VERSION 5.7 ;
BUSBITCHARS "[]" ;
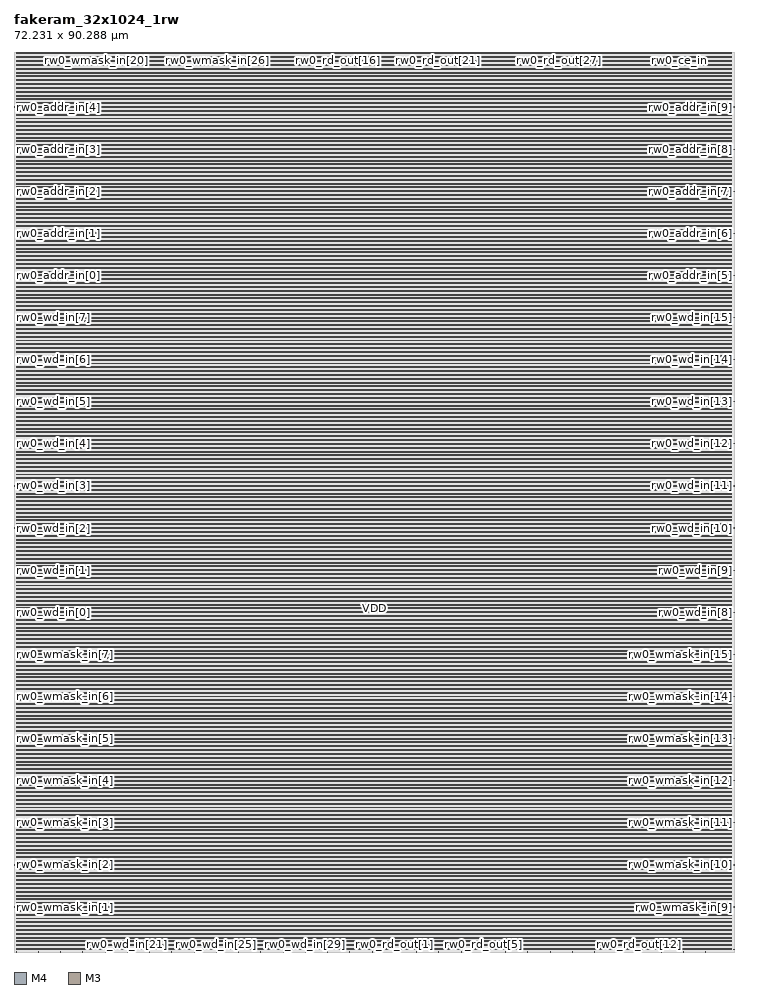
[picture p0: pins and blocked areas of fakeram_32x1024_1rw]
MACRO fakeram_32x1024_1rw
  FOREIGN fakeram_32x1024_1rw 0 0 ;
  SYMMETRY X Y R90 ;
  SIZE 72.231 BY 90.288 ;
  CLASS BLOCK ;
  PIN rw0_wmask_in[0]
    DIRECTION INPUT ;
    USE SIGNAL ;
    SHAPE ABUTMENT ;
    PORT
      LAYER M4 ;
      RECT 0.000 0.276 0.072 0.300 ;
    END
  END rw0_wmask_in[0]
  PIN rw0_wmask_in[1]
    DIRECTION INPUT ;
    USE SIGNAL ;
    SHAPE ABUTMENT ;
    PORT
      LAYER M4 ;
      RECT 0.000 4.500 0.072 4.524 ;
    END
  END rw0_wmask_in[1]
  PIN rw0_wmask_in[2]
    DIRECTION INPUT ;
    USE SIGNAL ;
    SHAPE ABUTMENT ;
    PORT
      LAYER M4 ;
      RECT 0.000 8.724 0.072 8.748 ;
    END
  END rw0_wmask_in[2]
  PIN rw0_wmask_in[3]
    DIRECTION INPUT ;
    USE SIGNAL ;
    SHAPE ABUTMENT ;
    PORT
      LAYER M4 ;
      RECT 0.000 12.948 0.072 12.972 ;
    END
  END rw0_wmask_in[3]
  PIN rw0_wmask_in[4]
    DIRECTION INPUT ;
    USE SIGNAL ;
    SHAPE ABUTMENT ;
    PORT
      LAYER M4 ;
      RECT 0.000 17.172 0.072 17.196 ;
    END
  END rw0_wmask_in[4]
  PIN rw0_wmask_in[5]
    DIRECTION INPUT ;
    USE SIGNAL ;
    SHAPE ABUTMENT ;
    PORT
      LAYER M4 ;
      RECT 0.000 21.396 0.072 21.420 ;
    END
  END rw0_wmask_in[5]
  PIN rw0_wmask_in[6]
    DIRECTION INPUT ;
    USE SIGNAL ;
    SHAPE ABUTMENT ;
    PORT
      LAYER M4 ;
      RECT 0.000 25.620 0.072 25.644 ;
    END
  END rw0_wmask_in[6]
  PIN rw0_wmask_in[7]
    DIRECTION INPUT ;
    USE SIGNAL ;
    SHAPE ABUTMENT ;
    PORT
      LAYER M4 ;
      RECT 0.000 29.844 0.072 29.868 ;
    END
  END rw0_wmask_in[7]
  PIN rw0_wmask_in[8]
    DIRECTION INPUT ;
    USE SIGNAL ;
    SHAPE ABUTMENT ;
    PORT
      LAYER M4 ;
      RECT 72.159 0.276 72.231 0.300 ;
    END
  END rw0_wmask_in[8]
  PIN rw0_wmask_in[9]
    DIRECTION INPUT ;
    USE SIGNAL ;
    SHAPE ABUTMENT ;
    PORT
      LAYER M4 ;
      RECT 72.159 4.500 72.231 4.524 ;
    END
  END rw0_wmask_in[9]
  PIN rw0_wmask_in[10]
    DIRECTION INPUT ;
    USE SIGNAL ;
    SHAPE ABUTMENT ;
    PORT
      LAYER M4 ;
      RECT 72.159 8.724 72.231 8.748 ;
    END
  END rw0_wmask_in[10]
  PIN rw0_wmask_in[11]
    DIRECTION INPUT ;
    USE SIGNAL ;
    SHAPE ABUTMENT ;
    PORT
      LAYER M4 ;
      RECT 72.159 12.948 72.231 12.972 ;
    END
  END rw0_wmask_in[11]
  PIN rw0_wmask_in[12]
    DIRECTION INPUT ;
    USE SIGNAL ;
    SHAPE ABUTMENT ;
    PORT
      LAYER M4 ;
      RECT 72.159 17.172 72.231 17.196 ;
    END
  END rw0_wmask_in[12]
  PIN rw0_wmask_in[13]
    DIRECTION INPUT ;
    USE SIGNAL ;
    SHAPE ABUTMENT ;
    PORT
      LAYER M4 ;
      RECT 72.159 21.396 72.231 21.420 ;
    END
  END rw0_wmask_in[13]
  PIN rw0_wmask_in[14]
    DIRECTION INPUT ;
    USE SIGNAL ;
    SHAPE ABUTMENT ;
    PORT
      LAYER M4 ;
      RECT 72.159 25.620 72.231 25.644 ;
    END
  END rw0_wmask_in[14]
  PIN rw0_wmask_in[15]
    DIRECTION INPUT ;
    USE SIGNAL ;
    SHAPE ABUTMENT ;
    PORT
      LAYER M4 ;
      RECT 72.159 29.844 72.231 29.868 ;
    END
  END rw0_wmask_in[15]
  PIN rw0_wmask_in[16]
    DIRECTION INPUT ;
    USE SIGNAL ;
    SHAPE ABUTMENT ;
    PORT
      LAYER M3 ;
      RECT 0.207 90.234 0.225 90.288 ;
    END
  END rw0_wmask_in[16]
  PIN rw0_wmask_in[17]
    DIRECTION INPUT ;
    USE SIGNAL ;
    SHAPE ABUTMENT ;
    PORT
      LAYER M3 ;
      RECT 2.223 90.234 2.241 90.288 ;
    END
  END rw0_wmask_in[17]
  PIN rw0_wmask_in[18]
    DIRECTION INPUT ;
    USE SIGNAL ;
    SHAPE ABUTMENT ;
    PORT
      LAYER M3 ;
      RECT 4.239 90.234 4.257 90.288 ;
    END
  END rw0_wmask_in[18]
  PIN rw0_wmask_in[19]
    DIRECTION INPUT ;
    USE SIGNAL ;
    SHAPE ABUTMENT ;
    PORT
      LAYER M3 ;
      RECT 6.255 90.234 6.273 90.288 ;
    END
  END rw0_wmask_in[19]
  PIN rw0_wmask_in[20]
    DIRECTION INPUT ;
    USE SIGNAL ;
    SHAPE ABUTMENT ;
    PORT
      LAYER M3 ;
      RECT 8.271 90.234 8.289 90.288 ;
    END
  END rw0_wmask_in[20]
  PIN rw0_wmask_in[21]
    DIRECTION INPUT ;
    USE SIGNAL ;
    SHAPE ABUTMENT ;
    PORT
      LAYER M3 ;
      RECT 10.287 90.234 10.305 90.288 ;
    END
  END rw0_wmask_in[21]
  PIN rw0_wmask_in[22]
    DIRECTION INPUT ;
    USE SIGNAL ;
    SHAPE ABUTMENT ;
    PORT
      LAYER M3 ;
      RECT 12.303 90.234 12.321 90.288 ;
    END
  END rw0_wmask_in[22]
  PIN rw0_wmask_in[23]
    DIRECTION INPUT ;
    USE SIGNAL ;
    SHAPE ABUTMENT ;
    PORT
      LAYER M3 ;
      RECT 14.319 90.234 14.337 90.288 ;
    END
  END rw0_wmask_in[23]
  PIN rw0_wmask_in[24]
    DIRECTION INPUT ;
    USE SIGNAL ;
    SHAPE ABUTMENT ;
    PORT
      LAYER M3 ;
      RECT 16.335 90.234 16.353 90.288 ;
    END
  END rw0_wmask_in[24]
  PIN rw0_wmask_in[25]
    DIRECTION INPUT ;
    USE SIGNAL ;
    SHAPE ABUTMENT ;
    PORT
      LAYER M3 ;
      RECT 18.351 90.234 18.369 90.288 ;
    END
  END rw0_wmask_in[25]
  PIN rw0_wmask_in[26]
    DIRECTION INPUT ;
    USE SIGNAL ;
    SHAPE ABUTMENT ;
    PORT
      LAYER M3 ;
      RECT 20.367 90.234 20.385 90.288 ;
    END
  END rw0_wmask_in[26]
  PIN rw0_wmask_in[27]
    DIRECTION INPUT ;
    USE SIGNAL ;
    SHAPE ABUTMENT ;
    PORT
      LAYER M3 ;
      RECT 22.383 90.234 22.401 90.288 ;
    END
  END rw0_wmask_in[27]
  PIN rw0_wmask_in[28]
    DIRECTION INPUT ;
    USE SIGNAL ;
    SHAPE ABUTMENT ;
    PORT
      LAYER M3 ;
      RECT 24.399 90.234 24.417 90.288 ;
    END
  END rw0_wmask_in[28]
  PIN rw0_wmask_in[29]
    DIRECTION INPUT ;
    USE SIGNAL ;
    SHAPE ABUTMENT ;
    PORT
      LAYER M3 ;
      RECT 26.415 90.234 26.433 90.288 ;
    END
  END rw0_wmask_in[29]
  PIN rw0_wmask_in[30]
    DIRECTION INPUT ;
    USE SIGNAL ;
    SHAPE ABUTMENT ;
    PORT
      LAYER M3 ;
      RECT 28.431 90.234 28.449 90.288 ;
    END
  END rw0_wmask_in[30]
  PIN rw0_wmask_in[31]
    DIRECTION INPUT ;
    USE SIGNAL ;
    SHAPE ABUTMENT ;
    PORT
      LAYER M3 ;
      RECT 30.447 90.234 30.465 90.288 ;
    END
  END rw0_wmask_in[31]
  PIN rw0_wd_in[0]
    DIRECTION INPUT ;
    USE SIGNAL ;
    SHAPE ABUTMENT ;
    PORT
      LAYER M4 ;
      RECT 0.000 34.068 0.072 34.092 ;
    END
  END rw0_wd_in[0]
  PIN rw0_wd_in[1]
    DIRECTION INPUT ;
    USE SIGNAL ;
    SHAPE ABUTMENT ;
    PORT
      LAYER M4 ;
      RECT 0.000 38.292 0.072 38.316 ;
    END
  END rw0_wd_in[1]
  PIN rw0_wd_in[2]
    DIRECTION INPUT ;
    USE SIGNAL ;
    SHAPE ABUTMENT ;
    PORT
      LAYER M4 ;
      RECT 0.000 42.516 0.072 42.540 ;
    END
  END rw0_wd_in[2]
  PIN rw0_wd_in[3]
    DIRECTION INPUT ;
    USE SIGNAL ;
    SHAPE ABUTMENT ;
    PORT
      LAYER M4 ;
      RECT 0.000 46.740 0.072 46.764 ;
    END
  END rw0_wd_in[3]
  PIN rw0_wd_in[4]
    DIRECTION INPUT ;
    USE SIGNAL ;
    SHAPE ABUTMENT ;
    PORT
      LAYER M4 ;
      RECT 0.000 50.964 0.072 50.988 ;
    END
  END rw0_wd_in[4]
  PIN rw0_wd_in[5]
    DIRECTION INPUT ;
    USE SIGNAL ;
    SHAPE ABUTMENT ;
    PORT
      LAYER M4 ;
      RECT 0.000 55.188 0.072 55.212 ;
    END
  END rw0_wd_in[5]
  PIN rw0_wd_in[6]
    DIRECTION INPUT ;
    USE SIGNAL ;
    SHAPE ABUTMENT ;
    PORT
      LAYER M4 ;
      RECT 0.000 59.412 0.072 59.436 ;
    END
  END rw0_wd_in[6]
  PIN rw0_wd_in[7]
    DIRECTION INPUT ;
    USE SIGNAL ;
    SHAPE ABUTMENT ;
    PORT
      LAYER M4 ;
      RECT 0.000 63.636 0.072 63.660 ;
    END
  END rw0_wd_in[7]
  PIN rw0_wd_in[8]
    DIRECTION INPUT ;
    USE SIGNAL ;
    SHAPE ABUTMENT ;
    PORT
      LAYER M4 ;
      RECT 72.159 34.068 72.231 34.092 ;
    END
  END rw0_wd_in[8]
  PIN rw0_wd_in[9]
    DIRECTION INPUT ;
    USE SIGNAL ;
    SHAPE ABUTMENT ;
    PORT
      LAYER M4 ;
      RECT 72.159 38.292 72.231 38.316 ;
    END
  END rw0_wd_in[9]
  PIN rw0_wd_in[10]
    DIRECTION INPUT ;
    USE SIGNAL ;
    SHAPE ABUTMENT ;
    PORT
      LAYER M4 ;
      RECT 72.159 42.516 72.231 42.540 ;
    END
  END rw0_wd_in[10]
  PIN rw0_wd_in[11]
    DIRECTION INPUT ;
    USE SIGNAL ;
    SHAPE ABUTMENT ;
    PORT
      LAYER M4 ;
      RECT 72.159 46.740 72.231 46.764 ;
    END
  END rw0_wd_in[11]
  PIN rw0_wd_in[12]
    DIRECTION INPUT ;
    USE SIGNAL ;
    SHAPE ABUTMENT ;
    PORT
      LAYER M4 ;
      RECT 72.159 50.964 72.231 50.988 ;
    END
  END rw0_wd_in[12]
  PIN rw0_wd_in[13]
    DIRECTION INPUT ;
    USE SIGNAL ;
    SHAPE ABUTMENT ;
    PORT
      LAYER M4 ;
      RECT 72.159 55.188 72.231 55.212 ;
    END
  END rw0_wd_in[13]
  PIN rw0_wd_in[14]
    DIRECTION INPUT ;
    USE SIGNAL ;
    SHAPE ABUTMENT ;
    PORT
      LAYER M4 ;
      RECT 72.159 59.412 72.231 59.436 ;
    END
  END rw0_wd_in[14]
  PIN rw0_wd_in[15]
    DIRECTION INPUT ;
    USE SIGNAL ;
    SHAPE ABUTMENT ;
    PORT
      LAYER M4 ;
      RECT 72.159 63.636 72.231 63.660 ;
    END
  END rw0_wd_in[15]
  PIN rw0_wd_in[16]
    DIRECTION INPUT ;
    USE SIGNAL ;
    SHAPE ABUTMENT ;
    PORT
      LAYER M3 ;
      RECT 0.207 0.000 0.225 0.054 ;
    END
  END rw0_wd_in[16]
  PIN rw0_wd_in[17]
    DIRECTION INPUT ;
    USE SIGNAL ;
    SHAPE ABUTMENT ;
    PORT
      LAYER M3 ;
      RECT 2.439 0.000 2.457 0.054 ;
    END
  END rw0_wd_in[17]
  PIN rw0_wd_in[18]
    DIRECTION INPUT ;
    USE SIGNAL ;
    SHAPE ABUTMENT ;
    PORT
      LAYER M3 ;
      RECT 4.671 0.000 4.689 0.054 ;
    END
  END rw0_wd_in[18]
  PIN rw0_wd_in[19]
    DIRECTION INPUT ;
    USE SIGNAL ;
    SHAPE ABUTMENT ;
    PORT
      LAYER M3 ;
      RECT 6.903 0.000 6.921 0.054 ;
    END
  END rw0_wd_in[19]
  PIN rw0_wd_in[20]
    DIRECTION INPUT ;
    USE SIGNAL ;
    SHAPE ABUTMENT ;
    PORT
      LAYER M3 ;
      RECT 9.135 0.000 9.153 0.054 ;
    END
  END rw0_wd_in[20]
  PIN rw0_wd_in[21]
    DIRECTION INPUT ;
    USE SIGNAL ;
    SHAPE ABUTMENT ;
    PORT
      LAYER M3 ;
      RECT 11.367 0.000 11.385 0.054 ;
    END
  END rw0_wd_in[21]
  PIN rw0_wd_in[22]
    DIRECTION INPUT ;
    USE SIGNAL ;
    SHAPE ABUTMENT ;
    PORT
      LAYER M3 ;
      RECT 13.599 0.000 13.617 0.054 ;
    END
  END rw0_wd_in[22]
  PIN rw0_wd_in[23]
    DIRECTION INPUT ;
    USE SIGNAL ;
    SHAPE ABUTMENT ;
    PORT
      LAYER M3 ;
      RECT 15.831 0.000 15.849 0.054 ;
    END
  END rw0_wd_in[23]
  PIN rw0_wd_in[24]
    DIRECTION INPUT ;
    USE SIGNAL ;
    SHAPE ABUTMENT ;
    PORT
      LAYER M3 ;
      RECT 18.063 0.000 18.081 0.054 ;
    END
  END rw0_wd_in[24]
  PIN rw0_wd_in[25]
    DIRECTION INPUT ;
    USE SIGNAL ;
    SHAPE ABUTMENT ;
    PORT
      LAYER M3 ;
      RECT 20.295 0.000 20.313 0.054 ;
    END
  END rw0_wd_in[25]
  PIN rw0_wd_in[26]
    DIRECTION INPUT ;
    USE SIGNAL ;
    SHAPE ABUTMENT ;
    PORT
      LAYER M3 ;
      RECT 22.527 0.000 22.545 0.054 ;
    END
  END rw0_wd_in[26]
  PIN rw0_wd_in[27]
    DIRECTION INPUT ;
    USE SIGNAL ;
    SHAPE ABUTMENT ;
    PORT
      LAYER M3 ;
      RECT 24.759 0.000 24.777 0.054 ;
    END
  END rw0_wd_in[27]
  PIN rw0_wd_in[28]
    DIRECTION INPUT ;
    USE SIGNAL ;
    SHAPE ABUTMENT ;
    PORT
      LAYER M3 ;
      RECT 26.991 0.000 27.009 0.054 ;
    END
  END rw0_wd_in[28]
  PIN rw0_wd_in[29]
    DIRECTION INPUT ;
    USE SIGNAL ;
    SHAPE ABUTMENT ;
    PORT
      LAYER M3 ;
      RECT 29.223 0.000 29.241 0.054 ;
    END
  END rw0_wd_in[29]
  PIN rw0_wd_in[30]
    DIRECTION INPUT ;
    USE SIGNAL ;
    SHAPE ABUTMENT ;
    PORT
      LAYER M3 ;
      RECT 31.455 0.000 31.473 0.054 ;
    END
  END rw0_wd_in[30]
  PIN rw0_wd_in[31]
    DIRECTION INPUT ;
    USE SIGNAL ;
    SHAPE ABUTMENT ;
    PORT
      LAYER M3 ;
      RECT 33.687 0.000 33.705 0.054 ;
    END
  END rw0_wd_in[31]
  PIN rw0_rd_out[0]
    DIRECTION OUTPUT ;
    USE SIGNAL ;
    SHAPE ABUTMENT ;
    PORT
      LAYER M3 ;
      RECT 35.919 0.000 35.937 0.054 ;
    END
  END rw0_rd_out[0]
  PIN rw0_rd_out[1]
    DIRECTION OUTPUT ;
    USE SIGNAL ;
    SHAPE ABUTMENT ;
    PORT
      LAYER M3 ;
      RECT 38.151 0.000 38.169 0.054 ;
    END
  END rw0_rd_out[1]
  PIN rw0_rd_out[2]
    DIRECTION OUTPUT ;
    USE SIGNAL ;
    SHAPE ABUTMENT ;
    PORT
      LAYER M3 ;
      RECT 40.383 0.000 40.401 0.054 ;
    END
  END rw0_rd_out[2]
  PIN rw0_rd_out[3]
    DIRECTION OUTPUT ;
    USE SIGNAL ;
    SHAPE ABUTMENT ;
    PORT
      LAYER M3 ;
      RECT 42.615 0.000 42.633 0.054 ;
    END
  END rw0_rd_out[3]
  PIN rw0_rd_out[4]
    DIRECTION OUTPUT ;
    USE SIGNAL ;
    SHAPE ABUTMENT ;
    PORT
      LAYER M3 ;
      RECT 44.847 0.000 44.865 0.054 ;
    END
  END rw0_rd_out[4]
  PIN rw0_rd_out[5]
    DIRECTION OUTPUT ;
    USE SIGNAL ;
    SHAPE ABUTMENT ;
    PORT
      LAYER M3 ;
      RECT 47.079 0.000 47.097 0.054 ;
    END
  END rw0_rd_out[5]
  PIN rw0_rd_out[6]
    DIRECTION OUTPUT ;
    USE SIGNAL ;
    SHAPE ABUTMENT ;
    PORT
      LAYER M3 ;
      RECT 49.311 0.000 49.329 0.054 ;
    END
  END rw0_rd_out[6]
  PIN rw0_rd_out[7]
    DIRECTION OUTPUT ;
    USE SIGNAL ;
    SHAPE ABUTMENT ;
    PORT
      LAYER M3 ;
      RECT 51.543 0.000 51.561 0.054 ;
    END
  END rw0_rd_out[7]
  PIN rw0_rd_out[8]
    DIRECTION OUTPUT ;
    USE SIGNAL ;
    SHAPE ABUTMENT ;
    PORT
      LAYER M3 ;
      RECT 53.775 0.000 53.793 0.054 ;
    END
  END rw0_rd_out[8]
  PIN rw0_rd_out[9]
    DIRECTION OUTPUT ;
    USE SIGNAL ;
    SHAPE ABUTMENT ;
    PORT
      LAYER M3 ;
      RECT 56.007 0.000 56.025 0.054 ;
    END
  END rw0_rd_out[9]
  PIN rw0_rd_out[10]
    DIRECTION OUTPUT ;
    USE SIGNAL ;
    SHAPE ABUTMENT ;
    PORT
      LAYER M3 ;
      RECT 58.239 0.000 58.257 0.054 ;
    END
  END rw0_rd_out[10]
  PIN rw0_rd_out[11]
    DIRECTION OUTPUT ;
    USE SIGNAL ;
    SHAPE ABUTMENT ;
    PORT
      LAYER M3 ;
      RECT 60.471 0.000 60.489 0.054 ;
    END
  END rw0_rd_out[11]
  PIN rw0_rd_out[12]
    DIRECTION OUTPUT ;
    USE SIGNAL ;
    SHAPE ABUTMENT ;
    PORT
      LAYER M3 ;
      RECT 62.703 0.000 62.721 0.054 ;
    END
  END rw0_rd_out[12]
  PIN rw0_rd_out[13]
    DIRECTION OUTPUT ;
    USE SIGNAL ;
    SHAPE ABUTMENT ;
    PORT
      LAYER M3 ;
      RECT 64.935 0.000 64.953 0.054 ;
    END
  END rw0_rd_out[13]
  PIN rw0_rd_out[14]
    DIRECTION OUTPUT ;
    USE SIGNAL ;
    SHAPE ABUTMENT ;
    PORT
      LAYER M3 ;
      RECT 67.167 0.000 67.185 0.054 ;
    END
  END rw0_rd_out[14]
  PIN rw0_rd_out[15]
    DIRECTION OUTPUT ;
    USE SIGNAL ;
    SHAPE ABUTMENT ;
    PORT
      LAYER M3 ;
      RECT 69.399 0.000 69.417 0.054 ;
    END
  END rw0_rd_out[15]
  PIN rw0_rd_out[16]
    DIRECTION OUTPUT ;
    USE SIGNAL ;
    SHAPE ABUTMENT ;
    PORT
      LAYER M3 ;
      RECT 32.463 90.234 32.481 90.288 ;
    END
  END rw0_rd_out[16]
  PIN rw0_rd_out[17]
    DIRECTION OUTPUT ;
    USE SIGNAL ;
    SHAPE ABUTMENT ;
    PORT
      LAYER M3 ;
      RECT 34.479 90.234 34.497 90.288 ;
    END
  END rw0_rd_out[17]
  PIN rw0_rd_out[18]
    DIRECTION OUTPUT ;
    USE SIGNAL ;
    SHAPE ABUTMENT ;
    PORT
      LAYER M3 ;
      RECT 36.495 90.234 36.513 90.288 ;
    END
  END rw0_rd_out[18]
  PIN rw0_rd_out[19]
    DIRECTION OUTPUT ;
    USE SIGNAL ;
    SHAPE ABUTMENT ;
    PORT
      LAYER M3 ;
      RECT 38.511 90.234 38.529 90.288 ;
    END
  END rw0_rd_out[19]
  PIN rw0_rd_out[20]
    DIRECTION OUTPUT ;
    USE SIGNAL ;
    SHAPE ABUTMENT ;
    PORT
      LAYER M3 ;
      RECT 40.527 90.234 40.545 90.288 ;
    END
  END rw0_rd_out[20]
  PIN rw0_rd_out[21]
    DIRECTION OUTPUT ;
    USE SIGNAL ;
    SHAPE ABUTMENT ;
    PORT
      LAYER M3 ;
      RECT 42.543 90.234 42.561 90.288 ;
    END
  END rw0_rd_out[21]
  PIN rw0_rd_out[22]
    DIRECTION OUTPUT ;
    USE SIGNAL ;
    SHAPE ABUTMENT ;
    PORT
      LAYER M3 ;
      RECT 44.559 90.234 44.577 90.288 ;
    END
  END rw0_rd_out[22]
  PIN rw0_rd_out[23]
    DIRECTION OUTPUT ;
    USE SIGNAL ;
    SHAPE ABUTMENT ;
    PORT
      LAYER M3 ;
      RECT 46.575 90.234 46.593 90.288 ;
    END
  END rw0_rd_out[23]
  PIN rw0_rd_out[24]
    DIRECTION OUTPUT ;
    USE SIGNAL ;
    SHAPE ABUTMENT ;
    PORT
      LAYER M3 ;
      RECT 48.591 90.234 48.609 90.288 ;
    END
  END rw0_rd_out[24]
  PIN rw0_rd_out[25]
    DIRECTION OUTPUT ;
    USE SIGNAL ;
    SHAPE ABUTMENT ;
    PORT
      LAYER M3 ;
      RECT 50.607 90.234 50.625 90.288 ;
    END
  END rw0_rd_out[25]
  PIN rw0_rd_out[26]
    DIRECTION OUTPUT ;
    USE SIGNAL ;
    SHAPE ABUTMENT ;
    PORT
      LAYER M3 ;
      RECT 52.623 90.234 52.641 90.288 ;
    END
  END rw0_rd_out[26]
  PIN rw0_rd_out[27]
    DIRECTION OUTPUT ;
    USE SIGNAL ;
    SHAPE ABUTMENT ;
    PORT
      LAYER M3 ;
      RECT 54.639 90.234 54.657 90.288 ;
    END
  END rw0_rd_out[27]
  PIN rw0_rd_out[28]
    DIRECTION OUTPUT ;
    USE SIGNAL ;
    SHAPE ABUTMENT ;
    PORT
      LAYER M3 ;
      RECT 56.655 90.234 56.673 90.288 ;
    END
  END rw0_rd_out[28]
  PIN rw0_rd_out[29]
    DIRECTION OUTPUT ;
    USE SIGNAL ;
    SHAPE ABUTMENT ;
    PORT
      LAYER M3 ;
      RECT 58.671 90.234 58.689 90.288 ;
    END
  END rw0_rd_out[29]
  PIN rw0_rd_out[30]
    DIRECTION OUTPUT ;
    USE SIGNAL ;
    SHAPE ABUTMENT ;
    PORT
      LAYER M3 ;
      RECT 60.687 90.234 60.705 90.288 ;
    END
  END rw0_rd_out[30]
  PIN rw0_rd_out[31]
    DIRECTION OUTPUT ;
    USE SIGNAL ;
    SHAPE ABUTMENT ;
    PORT
      LAYER M3 ;
      RECT 62.703 90.234 62.721 90.288 ;
    END
  END rw0_rd_out[31]
  PIN rw0_addr_in[0]
    DIRECTION INPUT ;
    USE SIGNAL ;
    SHAPE ABUTMENT ;
    PORT
      LAYER M4 ;
      RECT 0.000 67.860 0.072 67.884 ;
    END
  END rw0_addr_in[0]
  PIN rw0_addr_in[1]
    DIRECTION INPUT ;
    USE SIGNAL ;
    SHAPE ABUTMENT ;
    PORT
      LAYER M4 ;
      RECT 0.000 72.084 0.072 72.108 ;
    END
  END rw0_addr_in[1]
  PIN rw0_addr_in[2]
    DIRECTION INPUT ;
    USE SIGNAL ;
    SHAPE ABUTMENT ;
    PORT
      LAYER M4 ;
      RECT 0.000 76.308 0.072 76.332 ;
    END
  END rw0_addr_in[2]
  PIN rw0_addr_in[3]
    DIRECTION INPUT ;
    USE SIGNAL ;
    SHAPE ABUTMENT ;
    PORT
      LAYER M4 ;
      RECT 0.000 80.532 0.072 80.556 ;
    END
  END rw0_addr_in[3]
  PIN rw0_addr_in[4]
    DIRECTION INPUT ;
    USE SIGNAL ;
    SHAPE ABUTMENT ;
    PORT
      LAYER M4 ;
      RECT 0.000 84.756 0.072 84.780 ;
    END
  END rw0_addr_in[4]
  PIN rw0_addr_in[5]
    DIRECTION INPUT ;
    USE SIGNAL ;
    SHAPE ABUTMENT ;
    PORT
      LAYER M4 ;
      RECT 72.159 67.860 72.231 67.884 ;
    END
  END rw0_addr_in[5]
  PIN rw0_addr_in[6]
    DIRECTION INPUT ;
    USE SIGNAL ;
    SHAPE ABUTMENT ;
    PORT
      LAYER M4 ;
      RECT 72.159 72.084 72.231 72.108 ;
    END
  END rw0_addr_in[6]
  PIN rw0_addr_in[7]
    DIRECTION INPUT ;
    USE SIGNAL ;
    SHAPE ABUTMENT ;
    PORT
      LAYER M4 ;
      RECT 72.159 76.308 72.231 76.332 ;
    END
  END rw0_addr_in[7]
  PIN rw0_addr_in[8]
    DIRECTION INPUT ;
    USE SIGNAL ;
    SHAPE ABUTMENT ;
    PORT
      LAYER M4 ;
      RECT 72.159 80.532 72.231 80.556 ;
    END
  END rw0_addr_in[8]
  PIN rw0_addr_in[9]
    DIRECTION INPUT ;
    USE SIGNAL ;
    SHAPE ABUTMENT ;
    PORT
      LAYER M4 ;
      RECT 72.159 84.756 72.231 84.780 ;
    END
  END rw0_addr_in[9]
  PIN rw0_we_in
    DIRECTION INPUT ;
    USE SIGNAL ;
    SHAPE ABUTMENT ;
    PORT
      LAYER M3 ;
      RECT 64.719 90.234 64.737 90.288 ;
    END
  END rw0_we_in
  PIN rw0_ce_in
    DIRECTION INPUT ;
    USE SIGNAL ;
    SHAPE ABUTMENT ;
    PORT
      LAYER M3 ;
      RECT 66.735 90.234 66.753 90.288 ;
    END
  END rw0_ce_in
  PIN rw0_clk
    DIRECTION INPUT ;
    USE SIGNAL ;
    SHAPE ABUTMENT ;
    PORT
      LAYER M3 ;
      RECT 68.751 90.234 68.769 90.288 ;
    END
  END rw0_clk
  PIN VSS
    DIRECTION INOUT ;
    USE GROUND ;
    PORT
      LAYER M4 ;
      RECT 0.216 0.240 72.015 0.336 ;
      RECT 0.216 1.008 72.015 1.104 ;
      RECT 0.216 1.776 72.015 1.872 ;
      RECT 0.216 2.544 72.015 2.640 ;
      RECT 0.216 3.312 72.015 3.408 ;
      RECT 0.216 4.080 72.015 4.176 ;
      RECT 0.216 4.848 72.015 4.944 ;
      RECT 0.216 5.616 72.015 5.712 ;
      RECT 0.216 6.384 72.015 6.480 ;
      RECT 0.216 7.152 72.015 7.248 ;
      RECT 0.216 7.920 72.015 8.016 ;
      RECT 0.216 8.688 72.015 8.784 ;
      RECT 0.216 9.456 72.015 9.552 ;
      RECT 0.216 10.224 72.015 10.320 ;
      RECT 0.216 10.992 72.015 11.088 ;
      RECT 0.216 11.760 72.015 11.856 ;
      RECT 0.216 12.528 72.015 12.624 ;
      RECT 0.216 13.296 72.015 13.392 ;
      RECT 0.216 14.064 72.015 14.160 ;
      RECT 0.216 14.832 72.015 14.928 ;
      RECT 0.216 15.600 72.015 15.696 ;
      RECT 0.216 16.368 72.015 16.464 ;
      RECT 0.216 17.136 72.015 17.232 ;
      RECT 0.216 17.904 72.015 18.000 ;
      RECT 0.216 18.672 72.015 18.768 ;
      RECT 0.216 19.440 72.015 19.536 ;
      RECT 0.216 20.208 72.015 20.304 ;
      RECT 0.216 20.976 72.015 21.072 ;
      RECT 0.216 21.744 72.015 21.840 ;
      RECT 0.216 22.512 72.015 22.608 ;
      RECT 0.216 23.280 72.015 23.376 ;
      RECT 0.216 24.048 72.015 24.144 ;
      RECT 0.216 24.816 72.015 24.912 ;
      RECT 0.216 25.584 72.015 25.680 ;
      RECT 0.216 26.352 72.015 26.448 ;
      RECT 0.216 27.120 72.015 27.216 ;
      RECT 0.216 27.888 72.015 27.984 ;
      RECT 0.216 28.656 72.015 28.752 ;
      RECT 0.216 29.424 72.015 29.520 ;
      RECT 0.216 30.192 72.015 30.288 ;
      RECT 0.216 30.960 72.015 31.056 ;
      RECT 0.216 31.728 72.015 31.824 ;
      RECT 0.216 32.496 72.015 32.592 ;
      RECT 0.216 33.264 72.015 33.360 ;
      RECT 0.216 34.032 72.015 34.128 ;
      RECT 0.216 34.800 72.015 34.896 ;
      RECT 0.216 35.568 72.015 35.664 ;
      RECT 0.216 36.336 72.015 36.432 ;
      RECT 0.216 37.104 72.015 37.200 ;
      RECT 0.216 37.872 72.015 37.968 ;
      RECT 0.216 38.640 72.015 38.736 ;
      RECT 0.216 39.408 72.015 39.504 ;
      RECT 0.216 40.176 72.015 40.272 ;
      RECT 0.216 40.944 72.015 41.040 ;
      RECT 0.216 41.712 72.015 41.808 ;
      RECT 0.216 42.480 72.015 42.576 ;
      RECT 0.216 43.248 72.015 43.344 ;
      RECT 0.216 44.016 72.015 44.112 ;
      RECT 0.216 44.784 72.015 44.880 ;
      RECT 0.216 45.552 72.015 45.648 ;
      RECT 0.216 46.320 72.015 46.416 ;
      RECT 0.216 47.088 72.015 47.184 ;
      RECT 0.216 47.856 72.015 47.952 ;
      RECT 0.216 48.624 72.015 48.720 ;
      RECT 0.216 49.392 72.015 49.488 ;
      RECT 0.216 50.160 72.015 50.256 ;
      RECT 0.216 50.928 72.015 51.024 ;
      RECT 0.216 51.696 72.015 51.792 ;
      RECT 0.216 52.464 72.015 52.560 ;
      RECT 0.216 53.232 72.015 53.328 ;
      RECT 0.216 54.000 72.015 54.096 ;
      RECT 0.216 54.768 72.015 54.864 ;
      RECT 0.216 55.536 72.015 55.632 ;
      RECT 0.216 56.304 72.015 56.400 ;
      RECT 0.216 57.072 72.015 57.168 ;
      RECT 0.216 57.840 72.015 57.936 ;
      RECT 0.216 58.608 72.015 58.704 ;
      RECT 0.216 59.376 72.015 59.472 ;
      RECT 0.216 60.144 72.015 60.240 ;
      RECT 0.216 60.912 72.015 61.008 ;
      RECT 0.216 61.680 72.015 61.776 ;
      RECT 0.216 62.448 72.015 62.544 ;
      RECT 0.216 63.216 72.015 63.312 ;
      RECT 0.216 63.984 72.015 64.080 ;
      RECT 0.216 64.752 72.015 64.848 ;
      RECT 0.216 65.520 72.015 65.616 ;
      RECT 0.216 66.288 72.015 66.384 ;
      RECT 0.216 67.056 72.015 67.152 ;
      RECT 0.216 67.824 72.015 67.920 ;
      RECT 0.216 68.592 72.015 68.688 ;
      RECT 0.216 69.360 72.015 69.456 ;
      RECT 0.216 70.128 72.015 70.224 ;
      RECT 0.216 70.896 72.015 70.992 ;
      RECT 0.216 71.664 72.015 71.760 ;
      RECT 0.216 72.432 72.015 72.528 ;
      RECT 0.216 73.200 72.015 73.296 ;
      RECT 0.216 73.968 72.015 74.064 ;
      RECT 0.216 74.736 72.015 74.832 ;
      RECT 0.216 75.504 72.015 75.600 ;
      RECT 0.216 76.272 72.015 76.368 ;
      RECT 0.216 77.040 72.015 77.136 ;
      RECT 0.216 77.808 72.015 77.904 ;
      RECT 0.216 78.576 72.015 78.672 ;
      RECT 0.216 79.344 72.015 79.440 ;
      RECT 0.216 80.112 72.015 80.208 ;
      RECT 0.216 80.880 72.015 80.976 ;
      RECT 0.216 81.648 72.015 81.744 ;
      RECT 0.216 82.416 72.015 82.512 ;
      RECT 0.216 83.184 72.015 83.280 ;
      RECT 0.216 83.952 72.015 84.048 ;
      RECT 0.216 84.720 72.015 84.816 ;
      RECT 0.216 85.488 72.015 85.584 ;
      RECT 0.216 86.256 72.015 86.352 ;
      RECT 0.216 87.024 72.015 87.120 ;
      RECT 0.216 87.792 72.015 87.888 ;
      RECT 0.216 88.560 72.015 88.656 ;
      RECT 0.216 89.328 72.015 89.424 ;
      RECT 0.216 90.096 72.015 90.192 ;
    END
  END VSS
  PIN VDD
    DIRECTION INOUT ;
    USE POWER ;
    PORT
      LAYER M4 ;
      RECT 0.216 0.624 72.015 0.720 ;
      RECT 0.216 1.392 72.015 1.488 ;
      RECT 0.216 2.160 72.015 2.256 ;
      RECT 0.216 2.928 72.015 3.024 ;
      RECT 0.216 3.696 72.015 3.792 ;
      RECT 0.216 4.464 72.015 4.560 ;
      RECT 0.216 5.232 72.015 5.328 ;
      RECT 0.216 6.000 72.015 6.096 ;
      RECT 0.216 6.768 72.015 6.864 ;
      RECT 0.216 7.536 72.015 7.632 ;
      RECT 0.216 8.304 72.015 8.400 ;
      RECT 0.216 9.072 72.015 9.168 ;
      RECT 0.216 9.840 72.015 9.936 ;
      RECT 0.216 10.608 72.015 10.704 ;
      RECT 0.216 11.376 72.015 11.472 ;
      RECT 0.216 12.144 72.015 12.240 ;
      RECT 0.216 12.912 72.015 13.008 ;
      RECT 0.216 13.680 72.015 13.776 ;
      RECT 0.216 14.448 72.015 14.544 ;
      RECT 0.216 15.216 72.015 15.312 ;
      RECT 0.216 15.984 72.015 16.080 ;
      RECT 0.216 16.752 72.015 16.848 ;
      RECT 0.216 17.520 72.015 17.616 ;
      RECT 0.216 18.288 72.015 18.384 ;
      RECT 0.216 19.056 72.015 19.152 ;
      RECT 0.216 19.824 72.015 19.920 ;
      RECT 0.216 20.592 72.015 20.688 ;
      RECT 0.216 21.360 72.015 21.456 ;
      RECT 0.216 22.128 72.015 22.224 ;
      RECT 0.216 22.896 72.015 22.992 ;
      RECT 0.216 23.664 72.015 23.760 ;
      RECT 0.216 24.432 72.015 24.528 ;
      RECT 0.216 25.200 72.015 25.296 ;
      RECT 0.216 25.968 72.015 26.064 ;
      RECT 0.216 26.736 72.015 26.832 ;
      RECT 0.216 27.504 72.015 27.600 ;
      RECT 0.216 28.272 72.015 28.368 ;
      RECT 0.216 29.040 72.015 29.136 ;
      RECT 0.216 29.808 72.015 29.904 ;
      RECT 0.216 30.576 72.015 30.672 ;
      RECT 0.216 31.344 72.015 31.440 ;
      RECT 0.216 32.112 72.015 32.208 ;
      RECT 0.216 32.880 72.015 32.976 ;
      RECT 0.216 33.648 72.015 33.744 ;
      RECT 0.216 34.416 72.015 34.512 ;
      RECT 0.216 35.184 72.015 35.280 ;
      RECT 0.216 35.952 72.015 36.048 ;
      RECT 0.216 36.720 72.015 36.816 ;
      RECT 0.216 37.488 72.015 37.584 ;
      RECT 0.216 38.256 72.015 38.352 ;
      RECT 0.216 39.024 72.015 39.120 ;
      RECT 0.216 39.792 72.015 39.888 ;
      RECT 0.216 40.560 72.015 40.656 ;
      RECT 0.216 41.328 72.015 41.424 ;
      RECT 0.216 42.096 72.015 42.192 ;
      RECT 0.216 42.864 72.015 42.960 ;
      RECT 0.216 43.632 72.015 43.728 ;
      RECT 0.216 44.400 72.015 44.496 ;
      RECT 0.216 45.168 72.015 45.264 ;
      RECT 0.216 45.936 72.015 46.032 ;
      RECT 0.216 46.704 72.015 46.800 ;
      RECT 0.216 47.472 72.015 47.568 ;
      RECT 0.216 48.240 72.015 48.336 ;
      RECT 0.216 49.008 72.015 49.104 ;
      RECT 0.216 49.776 72.015 49.872 ;
      RECT 0.216 50.544 72.015 50.640 ;
      RECT 0.216 51.312 72.015 51.408 ;
      RECT 0.216 52.080 72.015 52.176 ;
      RECT 0.216 52.848 72.015 52.944 ;
      RECT 0.216 53.616 72.015 53.712 ;
      RECT 0.216 54.384 72.015 54.480 ;
      RECT 0.216 55.152 72.015 55.248 ;
      RECT 0.216 55.920 72.015 56.016 ;
      RECT 0.216 56.688 72.015 56.784 ;
      RECT 0.216 57.456 72.015 57.552 ;
      RECT 0.216 58.224 72.015 58.320 ;
      RECT 0.216 58.992 72.015 59.088 ;
      RECT 0.216 59.760 72.015 59.856 ;
      RECT 0.216 60.528 72.015 60.624 ;
      RECT 0.216 61.296 72.015 61.392 ;
      RECT 0.216 62.064 72.015 62.160 ;
      RECT 0.216 62.832 72.015 62.928 ;
      RECT 0.216 63.600 72.015 63.696 ;
      RECT 0.216 64.368 72.015 64.464 ;
      RECT 0.216 65.136 72.015 65.232 ;
      RECT 0.216 65.904 72.015 66.000 ;
      RECT 0.216 66.672 72.015 66.768 ;
      RECT 0.216 67.440 72.015 67.536 ;
      RECT 0.216 68.208 72.015 68.304 ;
      RECT 0.216 68.976 72.015 69.072 ;
      RECT 0.216 69.744 72.015 69.840 ;
      RECT 0.216 70.512 72.015 70.608 ;
      RECT 0.216 71.280 72.015 71.376 ;
      RECT 0.216 72.048 72.015 72.144 ;
      RECT 0.216 72.816 72.015 72.912 ;
      RECT 0.216 73.584 72.015 73.680 ;
      RECT 0.216 74.352 72.015 74.448 ;
      RECT 0.216 75.120 72.015 75.216 ;
      RECT 0.216 75.888 72.015 75.984 ;
      RECT 0.216 76.656 72.015 76.752 ;
      RECT 0.216 77.424 72.015 77.520 ;
      RECT 0.216 78.192 72.015 78.288 ;
      RECT 0.216 78.960 72.015 79.056 ;
      RECT 0.216 79.728 72.015 79.824 ;
      RECT 0.216 80.496 72.015 80.592 ;
      RECT 0.216 81.264 72.015 81.360 ;
      RECT 0.216 82.032 72.015 82.128 ;
      RECT 0.216 82.800 72.015 82.896 ;
      RECT 0.216 83.568 72.015 83.664 ;
      RECT 0.216 84.336 72.015 84.432 ;
      RECT 0.216 85.104 72.015 85.200 ;
      RECT 0.216 85.872 72.015 85.968 ;
      RECT 0.216 86.640 72.015 86.736 ;
      RECT 0.216 87.408 72.015 87.504 ;
      RECT 0.216 88.176 72.015 88.272 ;
      RECT 0.216 88.944 72.015 89.040 ;
      RECT 0.216 89.712 72.015 89.808 ;
    END
  END VDD
  OBS
    LAYER M1 ;
    RECT 0 0 72.231 90.288 ;
    LAYER M2 ;
    RECT 0 0 72.231 90.288 ;
    LAYER M3 ;
    RECT 0 0 72.231 90.288 ;
    LAYER M4 ;
    RECT 0 0 72.231 90.288 ;
  END
END fakeram_32x1024_1rw

END LIBRARY
